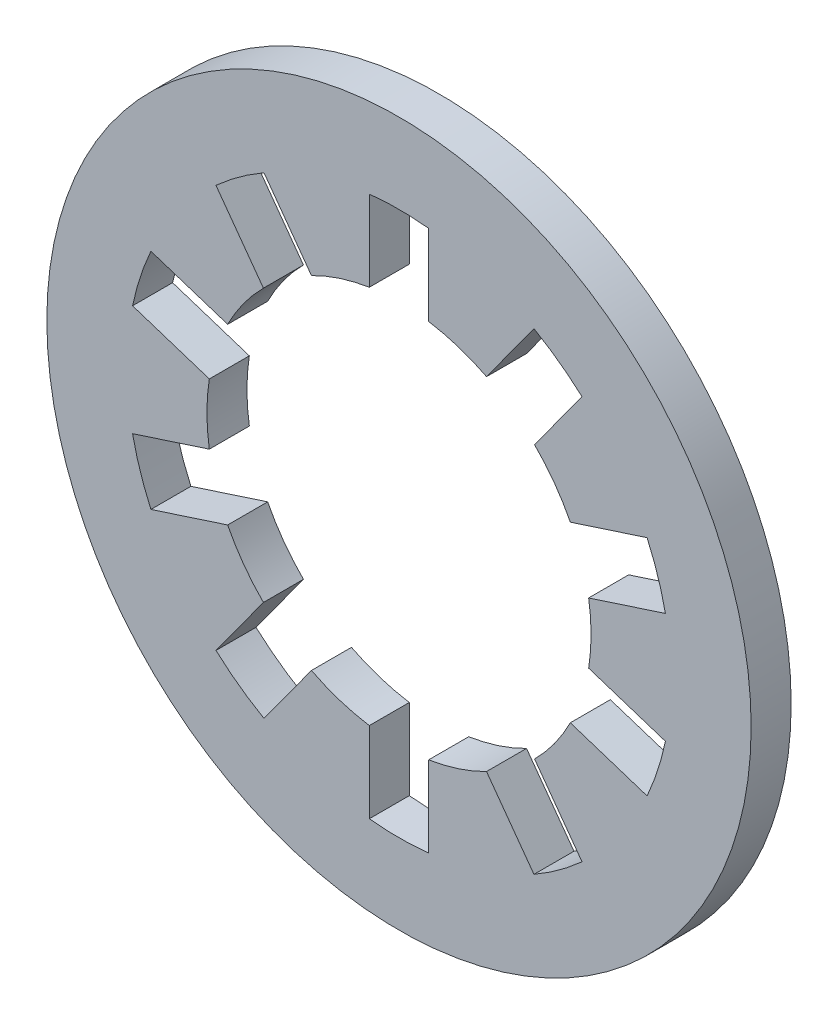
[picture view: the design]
ISO-10303-21;
HEADER;
FILE_DESCRIPTION(('STEP AP214'),'2;1');
FILE_NAME('part.step','',(''),(''),'','','');
FILE_SCHEMA(('AUTOMOTIVE_DESIGN { 1 0 10303 214 1 1 1 1 }'));
ENDSEC;
DATA;
#1=APPLICATION_CONTEXT('core data for automotive mechanical design processes');
#2=APPLICATION_PROTOCOL_DEFINITION('international standard','automotive_design',2000,#1);
#3=PRODUCT_CONTEXT('',#1,'mechanical');
#4=PRODUCT('Part','Part','',(#3));
#5=PRODUCT_RELATED_PRODUCT_CATEGORY('part','',(#4));
#6=PRODUCT_DEFINITION_FORMATION('','',#4);
#7=PRODUCT_DEFINITION_CONTEXT('part definition',#1,'design');
#8=PRODUCT_DEFINITION('design','',#6,#7);
#9=PRODUCT_DEFINITION_SHAPE('','',#8);
#10=(LENGTH_UNIT() NAMED_UNIT(*) SI_UNIT(.MILLI.,.METRE.));
#11=(NAMED_UNIT(*) PLANE_ANGLE_UNIT() SI_UNIT($,.RADIAN.));
#12=(NAMED_UNIT(*) SI_UNIT($,.STERADIAN.) SOLID_ANGLE_UNIT());
#13=UNCERTAINTY_MEASURE_WITH_UNIT(LENGTH_MEASURE(1.E-05),#10,'distance_accuracy_value','');
#14=(GEOMETRIC_REPRESENTATION_CONTEXT(3) GLOBAL_UNCERTAINTY_ASSIGNED_CONTEXT((#13)) GLOBAL_UNIT_ASSIGNED_CONTEXT((#10,
#11,#12)) REPRESENTATION_CONTEXT('',''));
#15=CARTESIAN_POINT('',(0.,0.,0.));
#16=DIRECTION('',(0.,0.,1.));
#17=DIRECTION('',(1.,0.,0.));
#18=AXIS2_PLACEMENT_3D('',#15,#16,#17);
#19=CARTESIAN_POINT('',(0.,0.,0.25));
#20=DIRECTION('',(0.,0.,1.));
#21=DIRECTION('',(1.,0.,0.));
#22=AXIS2_PLACEMENT_3D('',#19,#20,#21);
#23=PLANE('',#22);
#24=CARTESIAN_POINT('',(0.,0.,0.25));
#25=DIRECTION('',(0.,0.,1.));
#26=DIRECTION('',(1.,0.,0.));
#27=AXIS2_PLACEMENT_3D('',#24,#25,#26);
#28=CIRCLE('',#27,2.2);
#29=CARTESIAN_POINT('',(2.2,0.,0.25));
#30=VERTEX_POINT('',#29);
#31=EDGE_CURVE('E11',#30,#30,#28,.T.);
#32=ORIENTED_EDGE('',*,*,#31,.T.);
#33=EDGE_LOOP('',(#32));
#34=FACE_BOUND('',#33,.T.);
#35=CARTESIAN_POINT('',(0.,0.,0.25));
#36=DIRECTION('',(0.,0.,1.));
#37=DIRECTION('',(1.,0.,0.));
#38=AXIS2_PLACEMENT_3D('',#35,#36,#37);
#39=CIRCLE('',#38,1.2);
#40=CARTESIAN_POINT('',(-0.846872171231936,0.850180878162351,0.25));
#41=VERTEX_POINT('',#40);
#42=CARTESIAN_POINT('',(-1.07026795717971,0.542702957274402,0.25));
#43=VERTEX_POINT('',#42);
#44=EDGE_CURVE('E316',#41,#43,#39,.T.);
#45=ORIENTED_EDGE('',*,*,#44,.F.);
#46=DIRECTION('',(0.587785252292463,-0.809016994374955,0.));
#47=VECTOR('',#46,1.);
#48=CARTESIAN_POINT('',(-1.14327413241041,1.25814317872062,0.25));
#49=LINE('',#48,#47);
#50=CARTESIAN_POINT('',(-1.14327413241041,1.25814317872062,0.25));
#51=VERTEX_POINT('',#50);
#52=EDGE_CURVE('E305',#51,#41,#49,.T.);
#53=ORIENTED_EDGE('',*,*,#52,.F.);
#54=CARTESIAN_POINT('',(0.,0.,0.25));
#55=DIRECTION('',(0.,0.,1.));
#56=DIRECTION('',(0.809016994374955,0.587785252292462,0.));
#57=AXIS2_PLACEMENT_3D('',#54,#55,#56);
#58=CIRCLE('',#57,1.7);
#59=CARTESIAN_POINT('',(-0.84327413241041,1.47610593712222,0.25));
#60=VERTEX_POINT('',#59);
#61=EDGE_CURVE('E295',#60,#51,#58,.T.);
#62=ORIENTED_EDGE('',*,*,#61,.F.);
#63=DIRECTION('',(-0.587785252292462,0.809016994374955,0.));
#64=VECTOR('',#63,1.);
#65=CARTESIAN_POINT('',(-0.84327413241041,1.47610593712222,0.25));
#66=LINE('',#65,#64);
#67=CARTESIAN_POINT('',(-0.546872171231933,1.06814363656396,0.25));
#68=VERTEX_POINT('',#67);
#69=EDGE_CURVE('E317',#68,#60,#66,.T.);
#70=ORIENTED_EDGE('',*,*,#69,.F.);
#71=CARTESIAN_POINT('',(-0.185410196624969,1.18558975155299,0.25));
#72=VERTEX_POINT('',#71);
#73=EDGE_CURVE('E553',#72,#68,#39,.T.);
#74=ORIENTED_EDGE('',*,*,#73,.F.);
#75=DIRECTION('',(0.,-1.,0.));
#76=VECTOR('',#75,1.);
#77=CARTESIAN_POINT('',(-0.185410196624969,1.68985888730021,0.25));
#78=LINE('',#77,#76);
#79=CARTESIAN_POINT('',(-0.185410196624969,1.68985888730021,0.25));
#80=VERTEX_POINT('',#79);
#81=EDGE_CURVE('E530',#80,#72,#78,.T.);
#82=ORIENTED_EDGE('',*,*,#81,.F.);
#83=CARTESIAN_POINT('',(0.,0.,0.25));
#84=DIRECTION('',(0.,0.,1.));
#85=DIRECTION('',(1.,0.,0.));
#86=AXIS2_PLACEMENT_3D('',#83,#84,#85);
#87=CIRCLE('',#86,1.7);
#88=CARTESIAN_POINT('',(0.185410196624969,1.68985888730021,0.25));
#89=VERTEX_POINT('',#88);
#90=EDGE_CURVE('E528',#89,#80,#87,.T.);
#91=ORIENTED_EDGE('',*,*,#90,.F.);
#92=DIRECTION('',(0.,1.,0.));
#93=VECTOR('',#92,1.);
#94=CARTESIAN_POINT('',(0.185410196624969,1.68985888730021,0.25));
#95=LINE('',#94,#93);
#96=CARTESIAN_POINT('',(0.185410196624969,1.18558975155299,0.25));
#97=VERTEX_POINT('',#96);
#98=EDGE_CURVE('E533',#97,#89,#95,.T.);
#99=ORIENTED_EDGE('',*,*,#98,.F.);
#100=CARTESIAN_POINT('',(0.546872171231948,1.06814363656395,0.25));
#101=VERTEX_POINT('',#100);
#102=EDGE_CURVE('E556',#101,#97,#39,.T.);
#103=ORIENTED_EDGE('',*,*,#102,.F.);
#104=DIRECTION('',(-0.587785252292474,-0.809016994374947,0.));
#105=VECTOR('',#104,1.);
#106=CARTESIAN_POINT('',(0.843274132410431,1.47610593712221,0.25));
#107=LINE('',#106,#105);
#108=CARTESIAN_POINT('',(0.843274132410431,1.47610593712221,0.25));
#109=VERTEX_POINT('',#108);
#110=EDGE_CURVE('E505',#109,#101,#107,.T.);
#111=ORIENTED_EDGE('',*,*,#110,.F.);
#112=CARTESIAN_POINT('',(0.,0.,0.25));
#113=DIRECTION('',(0.,0.,1.));
#114=DIRECTION('',(0.809016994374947,-0.587785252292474,0.));
#115=AXIS2_PLACEMENT_3D('',#112,#113,#114);
#116=CIRCLE('',#115,1.7);
#117=CARTESIAN_POINT('',(1.14327413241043,1.2581431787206,0.25));
#118=VERTEX_POINT('',#117);
#119=EDGE_CURVE('E503',#118,#109,#116,.T.);
#120=ORIENTED_EDGE('',*,*,#119,.F.);
#121=DIRECTION('',(0.587785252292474,0.809016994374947,0.));
#122=VECTOR('',#121,1.);
#123=CARTESIAN_POINT('',(1.14327413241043,1.2581431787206,0.25));
#124=LINE('',#123,#122);
#125=CARTESIAN_POINT('',(0.846872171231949,0.850180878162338,0.25));
#126=VERTEX_POINT('',#125);
#127=EDGE_CURVE('E508',#126,#118,#124,.T.);
#128=ORIENTED_EDGE('',*,*,#127,.F.);
#129=CARTESIAN_POINT('',(1.07026795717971,0.542702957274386,0.25));
#130=VERTEX_POINT('',#129);
#131=EDGE_CURVE('E560',#130,#126,#39,.T.);
#132=ORIENTED_EDGE('',*,*,#131,.F.);
#133=DIRECTION('',(-0.951056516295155,-0.309016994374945,0.));
#134=VECTOR('',#133,1.);
#135=CARTESIAN_POINT('',(1.54985640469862,0.698530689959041,0.25));
#136=LINE('',#135,#134);
#137=CARTESIAN_POINT('',(1.54985640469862,0.698530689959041,0.25));
#138=VERTEX_POINT('',#137);
#139=EDGE_CURVE('E480',#138,#130,#136,.T.);
#140=ORIENTED_EDGE('',*,*,#139,.F.);
#141=CARTESIAN_POINT('',(0.,0.,0.25));
#142=DIRECTION('',(0.,0.,1.));
#143=DIRECTION('',(0.309016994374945,-0.951056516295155,0.));
#144=AXIS2_PLACEMENT_3D('',#141,#142,#143);
#145=CIRCLE('',#144,1.7);
#146=CARTESIAN_POINT('',(1.66444620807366,0.345859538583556,0.25));
#147=VERTEX_POINT('',#146);
#148=EDGE_CURVE('E478',#147,#138,#145,.T.);
#149=ORIENTED_EDGE('',*,*,#148,.F.);
#150=DIRECTION('',(0.951056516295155,0.309016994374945,0.));
#151=VECTOR('',#150,1.);
#152=CARTESIAN_POINT('',(1.66444620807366,0.345859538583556,0.25));
#153=LINE('',#152,#151);
#154=CARTESIAN_POINT('',(1.18485776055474,0.190031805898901,0.25));
#155=VERTEX_POINT('',#154);
#156=EDGE_CURVE('E483',#155,#147,#153,.T.);
#157=ORIENTED_EDGE('',*,*,#156,.F.);
#158=CARTESIAN_POINT('',(1.18485776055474,-0.19003180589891,0.25));
#159=VERTEX_POINT('',#158);
#160=EDGE_CURVE('E613',#159,#155,#39,.T.);
#161=ORIENTED_EDGE('',*,*,#160,.F.);
#162=DIRECTION('',(-0.951056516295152,0.309016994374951,0.));
#163=VECTOR('',#162,1.);
#164=CARTESIAN_POINT('',(1.66444620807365,-0.345859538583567,0.25));
#165=LINE('',#164,#163);
#166=CARTESIAN_POINT('',(1.66444620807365,-0.345859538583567,0.25));
#167=VERTEX_POINT('',#166);
#168=EDGE_CURVE('E455',#167,#159,#165,.T.);
#169=ORIENTED_EDGE('',*,*,#168,.F.);
#170=CARTESIAN_POINT('',(0.,0.,0.25));
#171=DIRECTION('',(0.,0.,1.));
#172=DIRECTION('',(-0.309016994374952,-0.951056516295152,0.));
#173=AXIS2_PLACEMENT_3D('',#170,#171,#172);
#174=CIRCLE('',#173,1.7);
#175=CARTESIAN_POINT('',(1.54985640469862,-0.698530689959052,0.25));
#176=VERTEX_POINT('',#175);
#177=EDGE_CURVE('E453',#176,#167,#174,.T.);
#178=ORIENTED_EDGE('',*,*,#177,.F.);
#179=DIRECTION('',(0.951056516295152,-0.309016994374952,0.));
#180=VECTOR('',#179,1.);
#181=CARTESIAN_POINT('',(1.54985640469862,-0.698530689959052,0.25));
#182=LINE('',#181,#180);
#183=CARTESIAN_POINT('',(1.07026795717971,-0.542702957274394,0.25));
#184=VERTEX_POINT('',#183);
#185=EDGE_CURVE('E458',#184,#176,#182,.T.);
#186=ORIENTED_EDGE('',*,*,#185,.F.);
#187=CARTESIAN_POINT('',(0.846872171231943,-0.850180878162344,0.25));
#188=VERTEX_POINT('',#187);
#189=EDGE_CURVE('E608',#188,#184,#39,.T.);
#190=ORIENTED_EDGE('',*,*,#189,.F.);
#191=DIRECTION('',(-0.587785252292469,0.809016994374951,0.));
#192=VECTOR('',#191,1.);
#193=CARTESIAN_POINT('',(1.14327413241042,-1.25814317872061,0.25));
#194=LINE('',#193,#192);
#195=CARTESIAN_POINT('',(1.14327413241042,-1.25814317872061,0.25));
#196=VERTEX_POINT('',#195);
#197=EDGE_CURVE('E430',#196,#188,#194,.T.);
#198=ORIENTED_EDGE('',*,*,#197,.F.);
#199=CARTESIAN_POINT('',(0.,0.,0.25));
#200=DIRECTION('',(0.,0.,1.));
#201=DIRECTION('',(-0.809016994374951,-0.587785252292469,0.));
#202=AXIS2_PLACEMENT_3D('',#199,#200,#201);
#203=CIRCLE('',#202,1.7);
#204=CARTESIAN_POINT('',(0.843274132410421,-1.47610593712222,0.25));
#205=VERTEX_POINT('',#204);
#206=EDGE_CURVE('E428',#205,#196,#203,.T.);
#207=ORIENTED_EDGE('',*,*,#206,.F.);
#208=DIRECTION('',(0.587785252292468,-0.809016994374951,0.));
#209=VECTOR('',#208,1.);
#210=CARTESIAN_POINT('',(0.843274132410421,-1.47610593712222,0.25));
#211=LINE('',#210,#209);
#212=CARTESIAN_POINT('',(0.546872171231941,-1.06814363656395,0.25));
#213=VERTEX_POINT('',#212);
#214=EDGE_CURVE('E433',#213,#205,#211,.T.);
#215=ORIENTED_EDGE('',*,*,#214,.F.);
#216=CARTESIAN_POINT('',(0.185410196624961,-1.185589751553,0.25));
#217=VERTEX_POINT('',#216);
#218=EDGE_CURVE('E603',#217,#213,#39,.T.);
#219=ORIENTED_EDGE('',*,*,#218,.F.);
#220=DIRECTION('',(0.,1.,0.));
#221=VECTOR('',#220,1.);
#222=CARTESIAN_POINT('',(0.185410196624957,-1.68985888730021,0.25));
#223=LINE('',#222,#221);
#224=CARTESIAN_POINT('',(0.185410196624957,-1.68985888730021,0.25));
#225=VERTEX_POINT('',#224);
#226=EDGE_CURVE('E405',#225,#217,#223,.T.);
#227=ORIENTED_EDGE('',*,*,#226,.F.);
#228=CARTESIAN_POINT('',(0.,0.,0.25));
#229=DIRECTION('',(0.,0.,1.));
#230=DIRECTION('',(-1.,0.,0.));
#231=AXIS2_PLACEMENT_3D('',#228,#229,#230);
#232=CIRCLE('',#231,1.7);
#233=CARTESIAN_POINT('',(-0.185410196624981,-1.6898588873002,0.25));
#234=VERTEX_POINT('',#233);
#235=EDGE_CURVE('E403',#234,#225,#232,.T.);
#236=ORIENTED_EDGE('',*,*,#235,.F.);
#237=DIRECTION('',(0.,-1.,0.));
#238=VECTOR('',#237,1.);
#239=CARTESIAN_POINT('',(-0.185410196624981,-1.6898588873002,0.25));
#240=LINE('',#239,#238);
#241=CARTESIAN_POINT('',(-0.185410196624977,-1.18558975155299,0.25));
#242=VERTEX_POINT('',#241);
#243=EDGE_CURVE('E408',#242,#234,#240,.T.);
#244=ORIENTED_EDGE('',*,*,#243,.F.);
#245=CARTESIAN_POINT('',(-0.546872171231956,-1.06814363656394,0.25));
#246=VERTEX_POINT('',#245);
#247=EDGE_CURVE('E598',#246,#242,#39,.T.);
#248=ORIENTED_EDGE('',*,*,#247,.F.);
#249=DIRECTION('',(0.58778525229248,0.809016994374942,0.));
#250=VECTOR('',#249,1.);
#251=CARTESIAN_POINT('',(-0.843274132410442,-1.4761059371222,0.25));
#252=LINE('',#251,#250);
#253=CARTESIAN_POINT('',(-0.843274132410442,-1.4761059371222,0.25));
#254=VERTEX_POINT('',#253);
#255=EDGE_CURVE('E380',#254,#246,#252,.T.);
#256=ORIENTED_EDGE('',*,*,#255,.F.);
#257=CARTESIAN_POINT('',(0.,0.,0.25));
#258=DIRECTION('',(0.,0.,1.));
#259=DIRECTION('',(-0.809016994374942,0.58778525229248,0.));
#260=AXIS2_PLACEMENT_3D('',#257,#258,#259);
#261=CIRCLE('',#260,1.7);
#262=CARTESIAN_POINT('',(-1.14327413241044,-1.25814317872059,0.25));
#263=VERTEX_POINT('',#262);
#264=EDGE_CURVE('E378',#263,#254,#261,.T.);
#265=ORIENTED_EDGE('',*,*,#264,.F.);
#266=DIRECTION('',(-0.58778525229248,-0.809016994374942,0.));
#267=VECTOR('',#266,1.);
#268=CARTESIAN_POINT('',(-1.14327413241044,-1.25814317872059,0.25));
#269=LINE('',#268,#267);
#270=CARTESIAN_POINT('',(-0.846872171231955,-0.850180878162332,0.25));
#271=VERTEX_POINT('',#270);
#272=EDGE_CURVE('E383',#271,#263,#269,.T.);
#273=ORIENTED_EDGE('',*,*,#272,.F.);
#274=CARTESIAN_POINT('',(-1.07026795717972,-0.542702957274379,0.25));
#275=VERTEX_POINT('',#274);
#276=EDGE_CURVE('E597',#275,#271,#39,.T.);
#277=ORIENTED_EDGE('',*,*,#276,.F.);
#278=DIRECTION('',(0.951056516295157,0.309016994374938,0.));
#279=VECTOR('',#278,1.);
#280=CARTESIAN_POINT('',(-1.54985640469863,-0.69853068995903,0.25));
#281=LINE('',#280,#279);
#282=CARTESIAN_POINT('',(-1.54985640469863,-0.69853068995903,0.25));
#283=VERTEX_POINT('',#282);
#284=EDGE_CURVE('E355',#283,#275,#281,.T.);
#285=ORIENTED_EDGE('',*,*,#284,.F.);
#286=CARTESIAN_POINT('',(0.,0.,0.25));
#287=DIRECTION('',(0.,0.,1.));
#288=DIRECTION('',(-0.309016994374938,0.951056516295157,0.));
#289=AXIS2_PLACEMENT_3D('',#286,#287,#288);
#290=CIRCLE('',#289,1.7);
#291=CARTESIAN_POINT('',(-1.66444620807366,-0.345859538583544,0.25));
#292=VERTEX_POINT('',#291);
#293=EDGE_CURVE('E353',#292,#283,#290,.T.);
#294=ORIENTED_EDGE('',*,*,#293,.F.);
#295=DIRECTION('',(-0.951056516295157,-0.309016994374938,0.));
#296=VECTOR('',#295,1.);
#297=CARTESIAN_POINT('',(-1.66444620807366,-0.345859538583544,0.25));
#298=LINE('',#297,#296);
#299=CARTESIAN_POINT('',(-1.18485776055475,-0.190031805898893,0.25));
#300=VERTEX_POINT('',#299);
#301=EDGE_CURVE('E358',#300,#292,#298,.T.);
#302=ORIENTED_EDGE('',*,*,#301,.F.);
#303=CARTESIAN_POINT('',(-1.18485776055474,0.190031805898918,0.25));
#304=VERTEX_POINT('',#303);
#305=EDGE_CURVE('E595',#304,#300,#39,.T.);
#306=ORIENTED_EDGE('',*,*,#305,.F.);
#307=DIRECTION('',(0.95105651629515,-0.309016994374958,0.));
#308=VECTOR('',#307,1.);
#309=CARTESIAN_POINT('',(-1.66444620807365,0.345859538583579,0.25));
#310=LINE('',#309,#308);
#311=CARTESIAN_POINT('',(-1.66444620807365,0.345859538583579,0.25));
#312=VERTEX_POINT('',#311);
#313=EDGE_CURVE('E331',#312,#304,#310,.T.);
#314=ORIENTED_EDGE('',*,*,#313,.F.);
#315=CARTESIAN_POINT('',(0.,0.,0.25));
#316=DIRECTION('',(0.,0.,1.));
#317=DIRECTION('',(0.309016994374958,0.95105651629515,0.));
#318=AXIS2_PLACEMENT_3D('',#315,#316,#317);
#319=CIRCLE('',#318,1.7);
#320=CARTESIAN_POINT('',(-1.54985640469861,0.698530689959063,0.25));
#321=VERTEX_POINT('',#320);
#322=EDGE_CURVE('E329',#321,#312,#319,.T.);
#323=ORIENTED_EDGE('',*,*,#322,.F.);
#324=DIRECTION('',(-0.95105651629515,0.309016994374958,0.));
#325=VECTOR('',#324,1.);
#326=CARTESIAN_POINT('',(-1.54985640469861,0.698530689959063,0.25));
#327=LINE('',#326,#325);
#328=EDGE_CURVE('E334',#43,#321,#327,.T.);
#329=ORIENTED_EDGE('',*,*,#328,.F.);
#330=EDGE_LOOP('',(#45,#53,#62,#70,#74,#82,#91,#99,#103,#111,#120,#128,#132,#140,#149,#157,#161,
#169,#178,#186,#190,#198,#207,#215,#219,#227,#236,#244,#248,#256,#265,#273,#277,#285,#294,#302,
#306,#314,#323,#329));
#331=FACE_BOUND('',#330,.T.);
#332=ADVANCED_FACE('F35',(#34,#331),#23,.T.);
#333=CARTESIAN_POINT('',(0.,0.,0.));
#334=DIRECTION('',(0.,0.,1.));
#335=DIRECTION('',(1.,0.,0.));
#336=AXIS2_PLACEMENT_3D('',#333,#334,#335);
#337=PLANE('',#336);
#338=CARTESIAN_POINT('',(0.,0.,0.));
#339=DIRECTION('',(0.,0.,1.));
#340=DIRECTION('',(1.,0.,0.));
#341=AXIS2_PLACEMENT_3D('',#338,#339,#340);
#342=CIRCLE('',#341,2.2);
#343=CARTESIAN_POINT('',(2.2,0.,0.));
#344=VERTEX_POINT('',#343);
#345=EDGE_CURVE('E39',#344,#344,#342,.T.);
#346=ORIENTED_EDGE('',*,*,#345,.F.);
#347=EDGE_LOOP('',(#346));
#348=FACE_BOUND('',#347,.T.);
#349=DIRECTION('',(0.587785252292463,-0.809016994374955,0.));
#350=VECTOR('',#349,1.);
#351=CARTESIAN_POINT('',(-1.14327413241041,1.25814317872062,0.));
#352=LINE('',#351,#350);
#353=CARTESIAN_POINT('',(-1.14327413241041,1.25814317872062,0.));
#354=VERTEX_POINT('',#353);
#355=CARTESIAN_POINT('',(-0.846872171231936,0.850180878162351,0.));
#356=VERTEX_POINT('',#355);
#357=EDGE_CURVE('E310',#354,#356,#352,.T.);
#358=ORIENTED_EDGE('',*,*,#357,.T.);
#359=CARTESIAN_POINT('',(0.,0.,0.));
#360=DIRECTION('',(0.,0.,1.));
#361=DIRECTION('',(1.,0.,0.));
#362=AXIS2_PLACEMENT_3D('',#359,#360,#361);
#363=CIRCLE('',#362,1.2);
#364=CARTESIAN_POINT('',(-1.07026795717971,0.542702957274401,0.));
#365=VERTEX_POINT('',#364);
#366=EDGE_CURVE('E58',#356,#365,#363,.T.);
#367=ORIENTED_EDGE('',*,*,#366,.T.);
#368=DIRECTION('',(-0.95105651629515,0.309016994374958,0.));
#369=VECTOR('',#368,1.);
#370=CARTESIAN_POINT('',(-1.54985640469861,0.698530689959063,0.));
#371=LINE('',#370,#369);
#372=CARTESIAN_POINT('',(-1.54985640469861,0.698530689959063,0.));
#373=VERTEX_POINT('',#372);
#374=EDGE_CURVE('E332',#365,#373,#371,.T.);
#375=ORIENTED_EDGE('',*,*,#374,.T.);
#376=CARTESIAN_POINT('',(0.,0.,0.));
#377=DIRECTION('',(0.,0.,1.));
#378=DIRECTION('',(0.309016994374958,0.95105651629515,0.));
#379=AXIS2_PLACEMENT_3D('',#376,#377,#378);
#380=CIRCLE('',#379,1.7);
#381=CARTESIAN_POINT('',(-1.66444620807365,0.345859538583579,0.));
#382=VERTEX_POINT('',#381);
#383=EDGE_CURVE('E311',#373,#382,#380,.T.);
#384=ORIENTED_EDGE('',*,*,#383,.T.);
#385=DIRECTION('',(0.95105651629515,-0.309016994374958,0.));
#386=VECTOR('',#385,1.);
#387=CARTESIAN_POINT('',(-1.66444620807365,0.345859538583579,0.));
#388=LINE('',#387,#386);
#389=CARTESIAN_POINT('',(-1.18485776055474,0.190031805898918,0.));
#390=VERTEX_POINT('',#389);
#391=EDGE_CURVE('E339',#382,#390,#388,.T.);
#392=ORIENTED_EDGE('',*,*,#391,.T.);
#393=CARTESIAN_POINT('',(-1.18485776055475,-0.190031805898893,0.));
#394=VERTEX_POINT('',#393);
#395=EDGE_CURVE('E561',#390,#394,#363,.T.);
#396=ORIENTED_EDGE('',*,*,#395,.T.);
#397=DIRECTION('',(-0.951056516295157,-0.309016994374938,0.));
#398=VECTOR('',#397,1.);
#399=CARTESIAN_POINT('',(-1.66444620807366,-0.345859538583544,0.));
#400=LINE('',#399,#398);
#401=CARTESIAN_POINT('',(-1.66444620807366,-0.345859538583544,0.));
#402=VERTEX_POINT('',#401);
#403=EDGE_CURVE('E356',#394,#402,#400,.T.);
#404=ORIENTED_EDGE('',*,*,#403,.T.);
#405=CARTESIAN_POINT('',(0.,0.,0.));
#406=DIRECTION('',(0.,0.,1.));
#407=DIRECTION('',(-0.309016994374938,0.951056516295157,0.));
#408=AXIS2_PLACEMENT_3D('',#405,#406,#407);
#409=CIRCLE('',#408,1.7);
#410=CARTESIAN_POINT('',(-1.54985640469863,-0.69853068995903,0.));
#411=VERTEX_POINT('',#410);
#412=EDGE_CURVE('E352',#402,#411,#409,.T.);
#413=ORIENTED_EDGE('',*,*,#412,.T.);
#414=DIRECTION('',(0.951056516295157,0.309016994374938,0.));
#415=VECTOR('',#414,1.);
#416=CARTESIAN_POINT('',(-1.54985640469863,-0.69853068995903,0.));
#417=LINE('',#416,#415);
#418=CARTESIAN_POINT('',(-1.07026795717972,-0.542702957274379,0.));
#419=VERTEX_POINT('',#418);
#420=EDGE_CURVE('E363',#411,#419,#417,.T.);
#421=ORIENTED_EDGE('',*,*,#420,.T.);
#422=CARTESIAN_POINT('',(-0.846872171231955,-0.850180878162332,0.));
#423=VERTEX_POINT('',#422);
#424=EDGE_CURVE('E577',#419,#423,#363,.T.);
#425=ORIENTED_EDGE('',*,*,#424,.T.);
#426=DIRECTION('',(-0.58778525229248,-0.809016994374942,0.));
#427=VECTOR('',#426,1.);
#428=CARTESIAN_POINT('',(-1.14327413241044,-1.25814317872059,0.));
#429=LINE('',#428,#427);
#430=CARTESIAN_POINT('',(-1.14327413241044,-1.25814317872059,0.));
#431=VERTEX_POINT('',#430);
#432=EDGE_CURVE('E381',#423,#431,#429,.T.);
#433=ORIENTED_EDGE('',*,*,#432,.T.);
#434=CARTESIAN_POINT('',(0.,0.,0.));
#435=DIRECTION('',(0.,0.,1.));
#436=DIRECTION('',(-0.809016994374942,0.58778525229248,0.));
#437=AXIS2_PLACEMENT_3D('',#434,#435,#436);
#438=CIRCLE('',#437,1.7);
#439=CARTESIAN_POINT('',(-0.843274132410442,-1.4761059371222,0.));
#440=VERTEX_POINT('',#439);
#441=EDGE_CURVE('E377',#431,#440,#438,.T.);
#442=ORIENTED_EDGE('',*,*,#441,.T.);
#443=DIRECTION('',(0.58778525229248,0.809016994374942,0.));
#444=VECTOR('',#443,1.);
#445=CARTESIAN_POINT('',(-0.843274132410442,-1.4761059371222,0.));
#446=LINE('',#445,#444);
#447=CARTESIAN_POINT('',(-0.546872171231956,-1.06814363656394,0.));
#448=VERTEX_POINT('',#447);
#449=EDGE_CURVE('E388',#440,#448,#446,.T.);
#450=ORIENTED_EDGE('',*,*,#449,.T.);
#451=CARTESIAN_POINT('',(-0.185410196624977,-1.18558975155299,0.));
#452=VERTEX_POINT('',#451);
#453=EDGE_CURVE('E574',#448,#452,#363,.T.);
#454=ORIENTED_EDGE('',*,*,#453,.T.);
#455=DIRECTION('',(0.,-1.,0.));
#456=VECTOR('',#455,1.);
#457=CARTESIAN_POINT('',(-0.185410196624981,-1.6898588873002,0.));
#458=LINE('',#457,#456);
#459=CARTESIAN_POINT('',(-0.185410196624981,-1.6898588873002,0.));
#460=VERTEX_POINT('',#459);
#461=EDGE_CURVE('E406',#452,#460,#458,.T.);
#462=ORIENTED_EDGE('',*,*,#461,.T.);
#463=CARTESIAN_POINT('',(0.,0.,0.));
#464=DIRECTION('',(0.,0.,1.));
#465=DIRECTION('',(-1.,0.,0.));
#466=AXIS2_PLACEMENT_3D('',#463,#464,#465);
#467=CIRCLE('',#466,1.7);
#468=CARTESIAN_POINT('',(0.185410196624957,-1.68985888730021,0.));
#469=VERTEX_POINT('',#468);
#470=EDGE_CURVE('E402',#460,#469,#467,.T.);
#471=ORIENTED_EDGE('',*,*,#470,.T.);
#472=DIRECTION('',(0.,1.,0.));
#473=VECTOR('',#472,1.);
#474=CARTESIAN_POINT('',(0.185410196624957,-1.68985888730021,0.));
#475=LINE('',#474,#473);
#476=CARTESIAN_POINT('',(0.185410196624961,-1.185589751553,0.));
#477=VERTEX_POINT('',#476);
#478=EDGE_CURVE('E413',#469,#477,#475,.T.);
#479=ORIENTED_EDGE('',*,*,#478,.T.);
#480=CARTESIAN_POINT('',(0.546872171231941,-1.06814363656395,0.));
#481=VERTEX_POINT('',#480);
#482=EDGE_CURVE('E571',#477,#481,#363,.T.);
#483=ORIENTED_EDGE('',*,*,#482,.T.);
#484=DIRECTION('',(0.587785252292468,-0.809016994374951,0.));
#485=VECTOR('',#484,1.);
#486=CARTESIAN_POINT('',(0.843274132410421,-1.47610593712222,0.));
#487=LINE('',#486,#485);
#488=CARTESIAN_POINT('',(0.843274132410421,-1.47610593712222,0.));
#489=VERTEX_POINT('',#488);
#490=EDGE_CURVE('E431',#481,#489,#487,.T.);
#491=ORIENTED_EDGE('',*,*,#490,.T.);
#492=CARTESIAN_POINT('',(0.,0.,0.));
#493=DIRECTION('',(0.,0.,1.));
#494=DIRECTION('',(-0.809016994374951,-0.587785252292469,0.));
#495=AXIS2_PLACEMENT_3D('',#492,#493,#494);
#496=CIRCLE('',#495,1.7);
#497=CARTESIAN_POINT('',(1.14327413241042,-1.25814317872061,0.));
#498=VERTEX_POINT('',#497);
#499=EDGE_CURVE('E427',#489,#498,#496,.T.);
#500=ORIENTED_EDGE('',*,*,#499,.T.);
#501=DIRECTION('',(-0.587785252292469,0.809016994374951,0.));
#502=VECTOR('',#501,1.);
#503=CARTESIAN_POINT('',(1.14327413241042,-1.25814317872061,0.));
#504=LINE('',#503,#502);
#505=CARTESIAN_POINT('',(0.846872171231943,-0.850180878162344,0.));
#506=VERTEX_POINT('',#505);
#507=EDGE_CURVE('E438',#498,#506,#504,.T.);
#508=ORIENTED_EDGE('',*,*,#507,.T.);
#509=CARTESIAN_POINT('',(1.07026795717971,-0.542702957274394,0.));
#510=VERTEX_POINT('',#509);
#511=EDGE_CURVE('E568',#506,#510,#363,.T.);
#512=ORIENTED_EDGE('',*,*,#511,.T.);
#513=DIRECTION('',(0.951056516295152,-0.309016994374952,0.));
#514=VECTOR('',#513,1.);
#515=CARTESIAN_POINT('',(1.54985640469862,-0.698530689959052,0.));
#516=LINE('',#515,#514);
#517=CARTESIAN_POINT('',(1.54985640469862,-0.698530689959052,0.));
#518=VERTEX_POINT('',#517);
#519=EDGE_CURVE('E456',#510,#518,#516,.T.);
#520=ORIENTED_EDGE('',*,*,#519,.T.);
#521=CARTESIAN_POINT('',(0.,0.,0.));
#522=DIRECTION('',(0.,0.,1.));
#523=DIRECTION('',(-0.309016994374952,-0.951056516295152,0.));
#524=AXIS2_PLACEMENT_3D('',#521,#522,#523);
#525=CIRCLE('',#524,1.7);
#526=CARTESIAN_POINT('',(1.66444620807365,-0.345859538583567,0.));
#527=VERTEX_POINT('',#526);
#528=EDGE_CURVE('E452',#518,#527,#525,.T.);
#529=ORIENTED_EDGE('',*,*,#528,.T.);
#530=DIRECTION('',(-0.951056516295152,0.309016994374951,0.));
#531=VECTOR('',#530,1.);
#532=CARTESIAN_POINT('',(1.66444620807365,-0.345859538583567,0.));
#533=LINE('',#532,#531);
#534=CARTESIAN_POINT('',(1.18485776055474,-0.19003180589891,0.));
#535=VERTEX_POINT('',#534);
#536=EDGE_CURVE('E463',#527,#535,#533,.T.);
#537=ORIENTED_EDGE('',*,*,#536,.T.);
#538=CARTESIAN_POINT('',(1.18485776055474,0.190031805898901,0.));
#539=VERTEX_POINT('',#538);
#540=EDGE_CURVE('E565',#535,#539,#363,.T.);
#541=ORIENTED_EDGE('',*,*,#540,.T.);
#542=DIRECTION('',(0.951056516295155,0.309016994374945,0.));
#543=VECTOR('',#542,1.);
#544=CARTESIAN_POINT('',(1.66444620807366,0.345859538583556,0.));
#545=LINE('',#544,#543);
#546=CARTESIAN_POINT('',(1.66444620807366,0.345859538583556,0.));
#547=VERTEX_POINT('',#546);
#548=EDGE_CURVE('E481',#539,#547,#545,.T.);
#549=ORIENTED_EDGE('',*,*,#548,.T.);
#550=CARTESIAN_POINT('',(0.,0.,0.));
#551=DIRECTION('',(0.,0.,1.));
#552=DIRECTION('',(0.309016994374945,-0.951056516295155,0.));
#553=AXIS2_PLACEMENT_3D('',#550,#551,#552);
#554=CIRCLE('',#553,1.7);
#555=CARTESIAN_POINT('',(1.54985640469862,0.698530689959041,0.));
#556=VERTEX_POINT('',#555);
#557=EDGE_CURVE('E477',#547,#556,#554,.T.);
#558=ORIENTED_EDGE('',*,*,#557,.T.);
#559=DIRECTION('',(-0.951056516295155,-0.309016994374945,0.));
#560=VECTOR('',#559,1.);
#561=CARTESIAN_POINT('',(1.54985640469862,0.698530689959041,0.));
#562=LINE('',#561,#560);
#563=CARTESIAN_POINT('',(1.07026795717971,0.542702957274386,0.));
#564=VERTEX_POINT('',#563);
#565=EDGE_CURVE('E488',#556,#564,#562,.T.);
#566=ORIENTED_EDGE('',*,*,#565,.T.);
#567=CARTESIAN_POINT('',(0.846872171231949,0.850180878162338,0.));
#568=VERTEX_POINT('',#567);
#569=EDGE_CURVE('E562',#564,#568,#363,.T.);
#570=ORIENTED_EDGE('',*,*,#569,.T.);
#571=DIRECTION('',(0.587785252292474,0.809016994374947,0.));
#572=VECTOR('',#571,1.);
#573=CARTESIAN_POINT('',(1.14327413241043,1.2581431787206,0.));
#574=LINE('',#573,#572);
#575=CARTESIAN_POINT('',(1.14327413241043,1.2581431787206,0.));
#576=VERTEX_POINT('',#575);
#577=EDGE_CURVE('E506',#568,#576,#574,.T.);
#578=ORIENTED_EDGE('',*,*,#577,.T.);
#579=CARTESIAN_POINT('',(0.,0.,0.));
#580=DIRECTION('',(0.,0.,1.));
#581=DIRECTION('',(0.809016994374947,-0.587785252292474,0.));
#582=AXIS2_PLACEMENT_3D('',#579,#580,#581);
#583=CIRCLE('',#582,1.7);
#584=CARTESIAN_POINT('',(0.843274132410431,1.47610593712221,0.));
#585=VERTEX_POINT('',#584);
#586=EDGE_CURVE('E502',#576,#585,#583,.T.);
#587=ORIENTED_EDGE('',*,*,#586,.T.);
#588=DIRECTION('',(-0.587785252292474,-0.809016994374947,0.));
#589=VECTOR('',#588,1.);
#590=CARTESIAN_POINT('',(0.843274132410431,1.47610593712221,0.));
#591=LINE('',#590,#589);
#592=CARTESIAN_POINT('',(0.546872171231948,1.06814363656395,0.));
#593=VERTEX_POINT('',#592);
#594=EDGE_CURVE('E513',#585,#593,#591,.T.);
#595=ORIENTED_EDGE('',*,*,#594,.T.);
#596=CARTESIAN_POINT('',(0.185410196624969,1.18558975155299,0.));
#597=VERTEX_POINT('',#596);
#598=EDGE_CURVE('E552',#593,#597,#363,.T.);
#599=ORIENTED_EDGE('',*,*,#598,.T.);
#600=DIRECTION('',(0.,1.,0.));
#601=VECTOR('',#600,1.);
#602=CARTESIAN_POINT('',(0.185410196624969,1.68985888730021,0.));
#603=LINE('',#602,#601);
#604=CARTESIAN_POINT('',(0.185410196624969,1.68985888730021,0.));
#605=VERTEX_POINT('',#604);
#606=EDGE_CURVE('E531',#597,#605,#603,.T.);
#607=ORIENTED_EDGE('',*,*,#606,.T.);
#608=CARTESIAN_POINT('',(0.,0.,0.));
#609=DIRECTION('',(0.,0.,1.));
#610=DIRECTION('',(1.,0.,0.));
#611=AXIS2_PLACEMENT_3D('',#608,#609,#610);
#612=CIRCLE('',#611,1.7);
#613=CARTESIAN_POINT('',(-0.185410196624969,1.68985888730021,0.));
#614=VERTEX_POINT('',#613);
#615=EDGE_CURVE('E527',#605,#614,#612,.T.);
#616=ORIENTED_EDGE('',*,*,#615,.T.);
#617=DIRECTION('',(0.,-1.,0.));
#618=VECTOR('',#617,1.);
#619=CARTESIAN_POINT('',(-0.185410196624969,1.68985888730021,0.));
#620=LINE('',#619,#618);
#621=CARTESIAN_POINT('',(-0.185410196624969,1.18558975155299,0.));
#622=VERTEX_POINT('',#621);
#623=EDGE_CURVE('E538',#614,#622,#620,.T.);
#624=ORIENTED_EDGE('',*,*,#623,.T.);
#625=CARTESIAN_POINT('',(-0.546872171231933,1.06814363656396,0.));
#626=VERTEX_POINT('',#625);
#627=EDGE_CURVE('E557',#622,#626,#363,.T.);
#628=ORIENTED_EDGE('',*,*,#627,.T.);
#629=DIRECTION('',(-0.587785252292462,0.809016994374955,0.));
#630=VECTOR('',#629,1.);
#631=CARTESIAN_POINT('',(-0.84327413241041,1.47610593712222,0.));
#632=LINE('',#631,#630);
#633=CARTESIAN_POINT('',(-0.84327413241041,1.47610593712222,0.));
#634=VERTEX_POINT('',#633);
#635=EDGE_CURVE('E50',#626,#634,#632,.T.);
#636=ORIENTED_EDGE('',*,*,#635,.T.);
#637=CARTESIAN_POINT('',(0.,0.,0.));
#638=DIRECTION('',(0.,0.,1.));
#639=DIRECTION('',(0.809016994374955,0.587785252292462,0.));
#640=AXIS2_PLACEMENT_3D('',#637,#638,#639);
#641=CIRCLE('',#640,1.7);
#642=EDGE_CURVE('E321',#634,#354,#641,.T.);
#643=ORIENTED_EDGE('',*,*,#642,.T.);
#644=EDGE_LOOP('',(#358,#367,#375,#384,#392,#396,#404,#413,#421,#425,#433,#442,#450,#454,#462,
#471,#479,#483,#491,#500,#508,#512,#520,#529,#537,#541,#549,#558,#566,#570,#578,#587,#595,#599,
#607,#616,#624,#628,#636,#643));
#645=FACE_BOUND('',#644,.T.);
#646=ADVANCED_FACE('F584',(#348,#645),#337,.F.);
#647=CARTESIAN_POINT('',(0.,0.,0.25));
#648=DIRECTION('',(0.,0.,-1.));
#649=DIRECTION('',(-1.,0.,0.));
#650=AXIS2_PLACEMENT_3D('',#647,#648,#649);
#651=CYLINDRICAL_SURFACE('',#650,1.2);
#652=ORIENTED_EDGE('',*,*,#366,.F.);
#653=DIRECTION('',(0.,0.,-1.));
#654=VECTOR('',#653,1.);
#655=CARTESIAN_POINT('',(-0.846872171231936,0.850180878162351,0.25));
#656=LINE('',#655,#654);
#657=EDGE_CURVE('E312',#41,#356,#656,.T.);
#658=ORIENTED_EDGE('',*,*,#657,.F.);
#659=ORIENTED_EDGE('',*,*,#44,.T.);
#660=DIRECTION('',(0.,0.,-1.));
#661=VECTOR('',#660,1.);
#662=CARTESIAN_POINT('',(-1.07026795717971,0.542702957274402,0.25));
#663=LINE('',#662,#661);
#664=EDGE_CURVE('E344',#43,#365,#663,.T.);
#665=ORIENTED_EDGE('',*,*,#664,.T.);
#666=EDGE_LOOP('',(#652,#658,#659,#665));
#667=FACE_BOUND('',#666,.T.);
#668=ADVANCED_FACE('F663',(#667),#651,.F.);
#669=ORIENTED_EDGE('',*,*,#73,.T.);
#670=DIRECTION('',(0.,0.,-1.));
#671=VECTOR('',#670,1.);
#672=CARTESIAN_POINT('',(-0.546872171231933,1.06814363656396,0.25));
#673=LINE('',#672,#671);
#674=EDGE_CURVE('E326',#68,#626,#673,.T.);
#675=ORIENTED_EDGE('',*,*,#674,.T.);
#676=ORIENTED_EDGE('',*,*,#627,.F.);
#677=DIRECTION('',(0.,0.,-1.));
#678=VECTOR('',#677,1.);
#679=CARTESIAN_POINT('',(-0.185410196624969,1.18558975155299,0.25));
#680=LINE('',#679,#678);
#681=EDGE_CURVE('E547',#72,#622,#680,.T.);
#682=ORIENTED_EDGE('',*,*,#681,.F.);
#683=EDGE_LOOP('',(#669,#675,#676,#682));
#684=FACE_BOUND('',#683,.T.);
#685=ADVANCED_FACE('F660',(#684),#651,.F.);
#686=ORIENTED_EDGE('',*,*,#395,.F.);
#687=DIRECTION('',(0.,0.,-1.));
#688=VECTOR('',#687,1.);
#689=CARTESIAN_POINT('',(-1.18485776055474,0.190031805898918,0.25));
#690=LINE('',#689,#688);
#691=EDGE_CURVE('E347',#304,#390,#690,.T.);
#692=ORIENTED_EDGE('',*,*,#691,.F.);
#693=ORIENTED_EDGE('',*,*,#305,.T.);
#694=DIRECTION('',(0.,0.,-1.));
#695=VECTOR('',#694,1.);
#696=CARTESIAN_POINT('',(-1.18485776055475,-0.190031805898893,0.25));
#697=LINE('',#696,#695);
#698=EDGE_CURVE('E369',#300,#394,#697,.T.);
#699=ORIENTED_EDGE('',*,*,#698,.T.);
#700=EDGE_LOOP('',(#686,#692,#693,#699));
#701=FACE_BOUND('',#700,.T.);
#702=ADVANCED_FACE('F593',(#701),#651,.F.);
#703=ORIENTED_EDGE('',*,*,#424,.F.);
#704=DIRECTION('',(0.,0.,-1.));
#705=VECTOR('',#704,1.);
#706=CARTESIAN_POINT('',(-1.07026795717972,-0.542702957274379,0.25));
#707=LINE('',#706,#705);
#708=EDGE_CURVE('E372',#275,#419,#707,.T.);
#709=ORIENTED_EDGE('',*,*,#708,.F.);
#710=ORIENTED_EDGE('',*,*,#276,.T.);
#711=DIRECTION('',(0.,0.,-1.));
#712=VECTOR('',#711,1.);
#713=CARTESIAN_POINT('',(-0.846872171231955,-0.850180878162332,0.25));
#714=LINE('',#713,#712);
#715=EDGE_CURVE('E394',#271,#423,#714,.T.);
#716=ORIENTED_EDGE('',*,*,#715,.T.);
#717=EDGE_LOOP('',(#703,#709,#710,#716));
#718=FACE_BOUND('',#717,.T.);
#719=ADVANCED_FACE('F998',(#718),#651,.F.);
#720=ORIENTED_EDGE('',*,*,#453,.F.);
#721=DIRECTION('',(0.,0.,-1.));
#722=VECTOR('',#721,1.);
#723=CARTESIAN_POINT('',(-0.546872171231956,-1.06814363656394,0.25));
#724=LINE('',#723,#722);
#725=EDGE_CURVE('E397',#246,#448,#724,.T.);
#726=ORIENTED_EDGE('',*,*,#725,.F.);
#727=ORIENTED_EDGE('',*,*,#247,.T.);
#728=DIRECTION('',(0.,0.,-1.));
#729=VECTOR('',#728,1.);
#730=CARTESIAN_POINT('',(-0.185410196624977,-1.18558975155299,0.25));
#731=LINE('',#730,#729);
#732=EDGE_CURVE('E419',#242,#452,#731,.T.);
#733=ORIENTED_EDGE('',*,*,#732,.T.);
#734=EDGE_LOOP('',(#720,#726,#727,#733));
#735=FACE_BOUND('',#734,.T.);
#736=ADVANCED_FACE('F1005',(#735),#651,.F.);
#737=ORIENTED_EDGE('',*,*,#482,.F.);
#738=DIRECTION('',(0.,0.,-1.));
#739=VECTOR('',#738,1.);
#740=CARTESIAN_POINT('',(0.185410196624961,-1.185589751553,0.25));
#741=LINE('',#740,#739);
#742=EDGE_CURVE('E422',#217,#477,#741,.T.);
#743=ORIENTED_EDGE('',*,*,#742,.F.);
#744=ORIENTED_EDGE('',*,*,#218,.T.);
#745=DIRECTION('',(0.,0.,-1.));
#746=VECTOR('',#745,1.);
#747=CARTESIAN_POINT('',(0.546872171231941,-1.06814363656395,0.25));
#748=LINE('',#747,#746);
#749=EDGE_CURVE('E444',#213,#481,#748,.T.);
#750=ORIENTED_EDGE('',*,*,#749,.T.);
#751=EDGE_LOOP('',(#737,#743,#744,#750));
#752=FACE_BOUND('',#751,.T.);
#753=ADVANCED_FACE('F1012',(#752),#651,.F.);
#754=ORIENTED_EDGE('',*,*,#511,.F.);
#755=DIRECTION('',(0.,0.,-1.));
#756=VECTOR('',#755,1.);
#757=CARTESIAN_POINT('',(0.846872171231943,-0.850180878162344,0.25));
#758=LINE('',#757,#756);
#759=EDGE_CURVE('E447',#188,#506,#758,.T.);
#760=ORIENTED_EDGE('',*,*,#759,.F.);
#761=ORIENTED_EDGE('',*,*,#189,.T.);
#762=DIRECTION('',(0.,0.,-1.));
#763=VECTOR('',#762,1.);
#764=CARTESIAN_POINT('',(1.07026795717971,-0.542702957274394,0.25));
#765=LINE('',#764,#763);
#766=EDGE_CURVE('E469',#184,#510,#765,.T.);
#767=ORIENTED_EDGE('',*,*,#766,.T.);
#768=EDGE_LOOP('',(#754,#760,#761,#767));
#769=FACE_BOUND('',#768,.T.);
#770=ADVANCED_FACE('F1019',(#769),#651,.F.);
#771=ORIENTED_EDGE('',*,*,#540,.F.);
#772=DIRECTION('',(0.,0.,-1.));
#773=VECTOR('',#772,1.);
#774=CARTESIAN_POINT('',(1.18485776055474,-0.19003180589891,0.25));
#775=LINE('',#774,#773);
#776=EDGE_CURVE('E472',#159,#535,#775,.T.);
#777=ORIENTED_EDGE('',*,*,#776,.F.);
#778=ORIENTED_EDGE('',*,*,#160,.T.);
#779=DIRECTION('',(0.,0.,-1.));
#780=VECTOR('',#779,1.);
#781=CARTESIAN_POINT('',(1.18485776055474,0.190031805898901,0.25));
#782=LINE('',#781,#780);
#783=EDGE_CURVE('E494',#155,#539,#782,.T.);
#784=ORIENTED_EDGE('',*,*,#783,.T.);
#785=EDGE_LOOP('',(#771,#777,#778,#784));
#786=FACE_BOUND('',#785,.T.);
#787=ADVANCED_FACE('F1026',(#786),#651,.F.);
#788=ORIENTED_EDGE('',*,*,#569,.F.);
#789=DIRECTION('',(0.,0.,-1.));
#790=VECTOR('',#789,1.);
#791=CARTESIAN_POINT('',(1.07026795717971,0.542702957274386,0.25));
#792=LINE('',#791,#790);
#793=EDGE_CURVE('E497',#130,#564,#792,.T.);
#794=ORIENTED_EDGE('',*,*,#793,.F.);
#795=ORIENTED_EDGE('',*,*,#131,.T.);
#796=DIRECTION('',(0.,0.,-1.));
#797=VECTOR('',#796,1.);
#798=CARTESIAN_POINT('',(0.846872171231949,0.850180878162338,0.25));
#799=LINE('',#798,#797);
#800=EDGE_CURVE('E519',#126,#568,#799,.T.);
#801=ORIENTED_EDGE('',*,*,#800,.T.);
#802=EDGE_LOOP('',(#788,#794,#795,#801));
#803=FACE_BOUND('',#802,.T.);
#804=ADVANCED_FACE('F626',(#803),#651,.F.);
#805=ORIENTED_EDGE('',*,*,#598,.F.);
#806=DIRECTION('',(0.,0.,-1.));
#807=VECTOR('',#806,1.);
#808=CARTESIAN_POINT('',(0.546872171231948,1.06814363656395,0.25));
#809=LINE('',#808,#807);
#810=EDGE_CURVE('E522',#101,#593,#809,.T.);
#811=ORIENTED_EDGE('',*,*,#810,.F.);
#812=ORIENTED_EDGE('',*,*,#102,.T.);
#813=DIRECTION('',(0.,0.,-1.));
#814=VECTOR('',#813,1.);
#815=CARTESIAN_POINT('',(0.185410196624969,1.18558975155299,0.25));
#816=LINE('',#815,#814);
#817=EDGE_CURVE('E544',#97,#597,#816,.T.);
#818=ORIENTED_EDGE('',*,*,#817,.T.);
#819=EDGE_LOOP('',(#805,#811,#812,#818));
#820=FACE_BOUND('',#819,.T.);
#821=ADVANCED_FACE('F643',(#820),#651,.F.);
#822=CARTESIAN_POINT('',(0.,0.,0.25));
#823=DIRECTION('',(0.,0.,-1.));
#824=DIRECTION('',(-1.,0.,0.));
#825=AXIS2_PLACEMENT_3D('',#822,#823,#824);
#826=CYLINDRICAL_SURFACE('',#825,2.2);
#827=ORIENTED_EDGE('',*,*,#31,.F.);
#828=EDGE_LOOP('',(#827));
#829=FACE_BOUND('',#828,.T.);
#830=ORIENTED_EDGE('',*,*,#345,.T.);
#831=EDGE_LOOP('',(#830));
#832=FACE_BOUND('',#831,.T.);
#833=ADVANCED_FACE('F37',(#829,#832),#826,.T.);
#834=CARTESIAN_POINT('',(0.,0.,0.25));
#835=DIRECTION('',(0.,0.,-1.));
#836=DIRECTION('',(-1.,0.,0.));
#837=AXIS2_PLACEMENT_3D('',#834,#835,#836);
#838=CYLINDRICAL_SURFACE('',#837,1.7);
#839=ORIENTED_EDGE('',*,*,#615,.F.);
#840=DIRECTION('',(0.,0.,-1.));
#841=VECTOR('',#840,1.);
#842=CARTESIAN_POINT('',(0.185410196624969,1.68985888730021,0.25));
#843=LINE('',#842,#841);
#844=EDGE_CURVE('E535',#89,#605,#843,.T.);
#845=ORIENTED_EDGE('',*,*,#844,.F.);
#846=ORIENTED_EDGE('',*,*,#90,.T.);
#847=DIRECTION('',(0.,0.,-1.));
#848=VECTOR('',#847,1.);
#849=CARTESIAN_POINT('',(-0.185410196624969,1.68985888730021,0.25));
#850=LINE('',#849,#848);
#851=EDGE_CURVE('E549',#80,#614,#850,.T.);
#852=ORIENTED_EDGE('',*,*,#851,.T.);
#853=EDGE_LOOP('',(#839,#845,#846,#852));
#854=FACE_BOUND('',#853,.T.);
#855=ADVANCED_FACE('F655',(#854),#838,.F.);
#856=CARTESIAN_POINT('',(-0.185410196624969,1.68985888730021,0.25));
#857=DIRECTION('',(1.,0.,0.));
#858=DIRECTION('',(0.,1.,0.));
#859=AXIS2_PLACEMENT_3D('',#856,#857,#858);
#860=PLANE('',#859);
#861=ORIENTED_EDGE('',*,*,#623,.F.);
#862=ORIENTED_EDGE('',*,*,#851,.F.);
#863=ORIENTED_EDGE('',*,*,#81,.T.);
#864=ORIENTED_EDGE('',*,*,#681,.T.);
#865=EDGE_LOOP('',(#861,#862,#863,#864));
#866=FACE_BOUND('',#865,.T.);
#867=ADVANCED_FACE('F657',(#866),#860,.T.);
#868=CARTESIAN_POINT('',(0.185410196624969,1.68985888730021,0.25));
#869=DIRECTION('',(-1.,0.,0.));
#870=DIRECTION('',(0.,-1.,0.));
#871=AXIS2_PLACEMENT_3D('',#868,#869,#870);
#872=PLANE('',#871);
#873=ORIENTED_EDGE('',*,*,#606,.F.);
#874=ORIENTED_EDGE('',*,*,#817,.F.);
#875=ORIENTED_EDGE('',*,*,#98,.T.);
#876=ORIENTED_EDGE('',*,*,#844,.T.);
#877=EDGE_LOOP('',(#873,#874,#875,#876));
#878=FACE_BOUND('',#877,.T.);
#879=ADVANCED_FACE('F647',(#878),#872,.T.);
#880=CARTESIAN_POINT('',(0.,0.,0.25));
#881=DIRECTION('',(0.,0.,-1.));
#882=DIRECTION('',(-1.,0.,0.));
#883=AXIS2_PLACEMENT_3D('',#880,#881,#882);
#884=CYLINDRICAL_SURFACE('',#883,1.7);
#885=ORIENTED_EDGE('',*,*,#586,.F.);
#886=DIRECTION('',(0.,0.,-1.));
#887=VECTOR('',#886,1.);
#888=CARTESIAN_POINT('',(1.14327413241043,1.2581431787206,0.25));
#889=LINE('',#888,#887);
#890=EDGE_CURVE('E510',#118,#576,#889,.T.);
#891=ORIENTED_EDGE('',*,*,#890,.F.);
#892=ORIENTED_EDGE('',*,*,#119,.T.);
#893=DIRECTION('',(0.,0.,-1.));
#894=VECTOR('',#893,1.);
#895=CARTESIAN_POINT('',(0.843274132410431,1.47610593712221,0.25));
#896=LINE('',#895,#894);
#897=EDGE_CURVE('E524',#109,#585,#896,.T.);
#898=ORIENTED_EDGE('',*,*,#897,.T.);
#899=EDGE_LOOP('',(#885,#891,#892,#898));
#900=FACE_BOUND('',#899,.T.);
#901=ADVANCED_FACE('F638',(#900),#884,.F.);
#902=CARTESIAN_POINT('',(0.843274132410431,1.47610593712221,0.25));
#903=DIRECTION('',(0.809016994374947,-0.587785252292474,0.));
#904=DIRECTION('',(0.587785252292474,0.809016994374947,0.));
#905=AXIS2_PLACEMENT_3D('',#902,#903,#904);
#906=PLANE('',#905);
#907=ORIENTED_EDGE('',*,*,#594,.F.);
#908=ORIENTED_EDGE('',*,*,#897,.F.);
#909=ORIENTED_EDGE('',*,*,#110,.T.);
#910=ORIENTED_EDGE('',*,*,#810,.T.);
#911=EDGE_LOOP('',(#907,#908,#909,#910));
#912=FACE_BOUND('',#911,.T.);
#913=ADVANCED_FACE('F640',(#912),#906,.T.);
#914=CARTESIAN_POINT('',(1.14327413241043,1.2581431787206,0.25));
#915=DIRECTION('',(-0.809016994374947,0.587785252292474,0.));
#916=DIRECTION('',(-0.587785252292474,-0.809016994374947,0.));
#917=AXIS2_PLACEMENT_3D('',#914,#915,#916);
#918=PLANE('',#917);
#919=ORIENTED_EDGE('',*,*,#577,.F.);
#920=ORIENTED_EDGE('',*,*,#800,.F.);
#921=ORIENTED_EDGE('',*,*,#127,.T.);
#922=ORIENTED_EDGE('',*,*,#890,.T.);
#923=EDGE_LOOP('',(#919,#920,#921,#922));
#924=FACE_BOUND('',#923,.T.);
#925=ADVANCED_FACE('F630',(#924),#918,.T.);
#926=CARTESIAN_POINT('',(0.,0.,0.25));
#927=DIRECTION('',(0.,0.,-1.));
#928=DIRECTION('',(-1.,0.,0.));
#929=AXIS2_PLACEMENT_3D('',#926,#927,#928);
#930=CYLINDRICAL_SURFACE('',#929,1.7);
#931=ORIENTED_EDGE('',*,*,#557,.F.);
#932=DIRECTION('',(0.,0.,-1.));
#933=VECTOR('',#932,1.);
#934=CARTESIAN_POINT('',(1.66444620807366,0.345859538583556,0.25));
#935=LINE('',#934,#933);
#936=EDGE_CURVE('E485',#147,#547,#935,.T.);
#937=ORIENTED_EDGE('',*,*,#936,.F.);
#938=ORIENTED_EDGE('',*,*,#148,.T.);
#939=DIRECTION('',(0.,0.,-1.));
#940=VECTOR('',#939,1.);
#941=CARTESIAN_POINT('',(1.54985640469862,0.698530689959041,0.25));
#942=LINE('',#941,#940);
#943=EDGE_CURVE('E499',#138,#556,#942,.T.);
#944=ORIENTED_EDGE('',*,*,#943,.T.);
#945=EDGE_LOOP('',(#931,#937,#938,#944));
#946=FACE_BOUND('',#945,.T.);
#947=ADVANCED_FACE('F705',(#946),#930,.F.);
#948=CARTESIAN_POINT('',(1.54985640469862,0.698530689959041,0.25));
#949=DIRECTION('',(0.309016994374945,-0.951056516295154,0.));
#950=DIRECTION('',(0.951056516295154,0.309016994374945,0.));
#951=AXIS2_PLACEMENT_3D('',#948,#949,#950);
#952=PLANE('',#951);
#953=ORIENTED_EDGE('',*,*,#565,.F.);
#954=ORIENTED_EDGE('',*,*,#943,.F.);
#955=ORIENTED_EDGE('',*,*,#139,.T.);
#956=ORIENTED_EDGE('',*,*,#793,.T.);
#957=EDGE_LOOP('',(#953,#954,#955,#956));
#958=FACE_BOUND('',#957,.T.);
#959=ADVANCED_FACE('F708',(#958),#952,.T.);
#960=CARTESIAN_POINT('',(1.66444620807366,0.345859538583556,0.25));
#961=DIRECTION('',(-0.309016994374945,0.951056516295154,0.));
#962=DIRECTION('',(-0.951056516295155,-0.309016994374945,0.));
#963=AXIS2_PLACEMENT_3D('',#960,#961,#962);
#964=PLANE('',#963);
#965=ORIENTED_EDGE('',*,*,#548,.F.);
#966=ORIENTED_EDGE('',*,*,#783,.F.);
#967=ORIENTED_EDGE('',*,*,#156,.T.);
#968=ORIENTED_EDGE('',*,*,#936,.T.);
#969=EDGE_LOOP('',(#965,#966,#967,#968));
#970=FACE_BOUND('',#969,.T.);
#971=ADVANCED_FACE('F712',(#970),#964,.T.);
#972=CARTESIAN_POINT('',(0.,0.,0.25));
#973=DIRECTION('',(0.,0.,-1.));
#974=DIRECTION('',(-1.,0.,0.));
#975=AXIS2_PLACEMENT_3D('',#972,#973,#974);
#976=CYLINDRICAL_SURFACE('',#975,1.7);
#977=ORIENTED_EDGE('',*,*,#528,.F.);
#978=DIRECTION('',(0.,0.,-1.));
#979=VECTOR('',#978,1.);
#980=CARTESIAN_POINT('',(1.54985640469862,-0.698530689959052,0.25));
#981=LINE('',#980,#979);
#982=EDGE_CURVE('E460',#176,#518,#981,.T.);
#983=ORIENTED_EDGE('',*,*,#982,.F.);
#984=ORIENTED_EDGE('',*,*,#177,.T.);
#985=DIRECTION('',(0.,0.,-1.));
#986=VECTOR('',#985,1.);
#987=CARTESIAN_POINT('',(1.66444620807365,-0.345859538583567,0.25));
#988=LINE('',#987,#986);
#989=EDGE_CURVE('E474',#167,#527,#988,.T.);
#990=ORIENTED_EDGE('',*,*,#989,.T.);
#991=EDGE_LOOP('',(#977,#983,#984,#990));
#992=FACE_BOUND('',#991,.T.);
#993=ADVANCED_FACE('F716',(#992),#976,.F.);
#994=CARTESIAN_POINT('',(1.66444620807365,-0.345859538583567,0.25));
#995=DIRECTION('',(-0.309016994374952,-0.951056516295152,0.));
#996=DIRECTION('',(0.951056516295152,-0.309016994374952,0.));
#997=AXIS2_PLACEMENT_3D('',#994,#995,#996);
#998=PLANE('',#997);
#999=ORIENTED_EDGE('',*,*,#536,.F.);
#1000=ORIENTED_EDGE('',*,*,#989,.F.);
#1001=ORIENTED_EDGE('',*,*,#168,.T.);
#1002=ORIENTED_EDGE('',*,*,#776,.T.);
#1003=EDGE_LOOP('',(#999,#1000,#1001,#1002));
#1004=FACE_BOUND('',#1003,.T.);
#1005=ADVANCED_FACE('F720',(#1004),#998,.T.);
#1006=CARTESIAN_POINT('',(1.54985640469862,-0.698530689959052,0.25));
#1007=DIRECTION('',(0.309016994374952,0.951056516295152,0.));
#1008=DIRECTION('',(-0.951056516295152,0.309016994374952,0.));
#1009=AXIS2_PLACEMENT_3D('',#1006,#1007,#1008);
#1010=PLANE('',#1009);
#1011=ORIENTED_EDGE('',*,*,#519,.F.);
#1012=ORIENTED_EDGE('',*,*,#766,.F.);
#1013=ORIENTED_EDGE('',*,*,#185,.T.);
#1014=ORIENTED_EDGE('',*,*,#982,.T.);
#1015=EDGE_LOOP('',(#1011,#1012,#1013,#1014));
#1016=FACE_BOUND('',#1015,.T.);
#1017=ADVANCED_FACE('F724',(#1016),#1010,.T.);
#1018=CARTESIAN_POINT('',(0.,0.,0.25));
#1019=DIRECTION('',(0.,0.,-1.));
#1020=DIRECTION('',(-1.,0.,0.));
#1021=AXIS2_PLACEMENT_3D('',#1018,#1019,#1020);
#1022=CYLINDRICAL_SURFACE('',#1021,1.7);
#1023=ORIENTED_EDGE('',*,*,#499,.F.);
#1024=DIRECTION('',(0.,0.,-1.));
#1025=VECTOR('',#1024,1.);
#1026=CARTESIAN_POINT('',(0.843274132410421,-1.47610593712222,0.25));
#1027=LINE('',#1026,#1025);
#1028=EDGE_CURVE('E435',#205,#489,#1027,.T.);
#1029=ORIENTED_EDGE('',*,*,#1028,.F.);
#1030=ORIENTED_EDGE('',*,*,#206,.T.);
#1031=DIRECTION('',(0.,0.,-1.));
#1032=VECTOR('',#1031,1.);
#1033=CARTESIAN_POINT('',(1.14327413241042,-1.25814317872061,0.25));
#1034=LINE('',#1033,#1032);
#1035=EDGE_CURVE('E449',#196,#498,#1034,.T.);
#1036=ORIENTED_EDGE('',*,*,#1035,.T.);
#1037=EDGE_LOOP('',(#1023,#1029,#1030,#1036));
#1038=FACE_BOUND('',#1037,.T.);
#1039=ADVANCED_FACE('F728',(#1038),#1022,.F.);
#1040=CARTESIAN_POINT('',(1.14327413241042,-1.25814317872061,0.25));
#1041=DIRECTION('',(-0.809016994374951,-0.587785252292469,0.));
#1042=DIRECTION('',(0.587785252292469,-0.809016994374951,0.));
#1043=AXIS2_PLACEMENT_3D('',#1040,#1041,#1042);
#1044=PLANE('',#1043);
#1045=ORIENTED_EDGE('',*,*,#507,.F.);
#1046=ORIENTED_EDGE('',*,*,#1035,.F.);
#1047=ORIENTED_EDGE('',*,*,#197,.T.);
#1048=ORIENTED_EDGE('',*,*,#759,.T.);
#1049=EDGE_LOOP('',(#1045,#1046,#1047,#1048));
#1050=FACE_BOUND('',#1049,.T.);
#1051=ADVANCED_FACE('F732',(#1050),#1044,.T.);
#1052=CARTESIAN_POINT('',(0.843274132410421,-1.47610593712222,0.25));
#1053=DIRECTION('',(0.809016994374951,0.587785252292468,0.));
#1054=DIRECTION('',(-0.587785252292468,0.809016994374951,0.));
#1055=AXIS2_PLACEMENT_3D('',#1052,#1053,#1054);
#1056=PLANE('',#1055);
#1057=ORIENTED_EDGE('',*,*,#490,.F.);
#1058=ORIENTED_EDGE('',*,*,#749,.F.);
#1059=ORIENTED_EDGE('',*,*,#214,.T.);
#1060=ORIENTED_EDGE('',*,*,#1028,.T.);
#1061=EDGE_LOOP('',(#1057,#1058,#1059,#1060));
#1062=FACE_BOUND('',#1061,.T.);
#1063=ADVANCED_FACE('F736',(#1062),#1056,.T.);
#1064=CARTESIAN_POINT('',(0.,0.,0.25));
#1065=DIRECTION('',(0.,0.,-1.));
#1066=DIRECTION('',(-1.,0.,0.));
#1067=AXIS2_PLACEMENT_3D('',#1064,#1065,#1066);
#1068=CYLINDRICAL_SURFACE('',#1067,1.7);
#1069=ORIENTED_EDGE('',*,*,#470,.F.);
#1070=DIRECTION('',(0.,0.,-1.));
#1071=VECTOR('',#1070,1.);
#1072=CARTESIAN_POINT('',(-0.185410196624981,-1.6898588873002,0.25));
#1073=LINE('',#1072,#1071);
#1074=EDGE_CURVE('E410',#234,#460,#1073,.T.);
#1075=ORIENTED_EDGE('',*,*,#1074,.F.);
#1076=ORIENTED_EDGE('',*,*,#235,.T.);
#1077=DIRECTION('',(0.,0.,-1.));
#1078=VECTOR('',#1077,1.);
#1079=CARTESIAN_POINT('',(0.185410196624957,-1.68985888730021,0.25));
#1080=LINE('',#1079,#1078);
#1081=EDGE_CURVE('E424',#225,#469,#1080,.T.);
#1082=ORIENTED_EDGE('',*,*,#1081,.T.);
#1083=EDGE_LOOP('',(#1069,#1075,#1076,#1082));
#1084=FACE_BOUND('',#1083,.T.);
#1085=ADVANCED_FACE('F740',(#1084),#1068,.F.);
#1086=CARTESIAN_POINT('',(0.185410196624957,-1.68985888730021,0.25));
#1087=DIRECTION('',(-1.,0.,0.));
#1088=DIRECTION('',(0.,-1.,0.));
#1089=AXIS2_PLACEMENT_3D('',#1086,#1087,#1088);
#1090=PLANE('',#1089);
#1091=ORIENTED_EDGE('',*,*,#478,.F.);
#1092=ORIENTED_EDGE('',*,*,#1081,.F.);
#1093=ORIENTED_EDGE('',*,*,#226,.T.);
#1094=ORIENTED_EDGE('',*,*,#742,.T.);
#1095=EDGE_LOOP('',(#1091,#1092,#1093,#1094));
#1096=FACE_BOUND('',#1095,.T.);
#1097=ADVANCED_FACE('F744',(#1096),#1090,.T.);
#1098=CARTESIAN_POINT('',(-0.185410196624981,-1.6898588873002,0.25));
#1099=DIRECTION('',(1.,0.,0.));
#1100=DIRECTION('',(0.,1.,0.));
#1101=AXIS2_PLACEMENT_3D('',#1098,#1099,#1100);
#1102=PLANE('',#1101);
#1103=ORIENTED_EDGE('',*,*,#461,.F.);
#1104=ORIENTED_EDGE('',*,*,#732,.F.);
#1105=ORIENTED_EDGE('',*,*,#243,.T.);
#1106=ORIENTED_EDGE('',*,*,#1074,.T.);
#1107=EDGE_LOOP('',(#1103,#1104,#1105,#1106));
#1108=FACE_BOUND('',#1107,.T.);
#1109=ADVANCED_FACE('F748',(#1108),#1102,.T.);
#1110=CARTESIAN_POINT('',(0.,0.,0.25));
#1111=DIRECTION('',(0.,0.,-1.));
#1112=DIRECTION('',(-1.,0.,0.));
#1113=AXIS2_PLACEMENT_3D('',#1110,#1111,#1112);
#1114=CYLINDRICAL_SURFACE('',#1113,1.7);
#1115=ORIENTED_EDGE('',*,*,#441,.F.);
#1116=DIRECTION('',(0.,0.,-1.));
#1117=VECTOR('',#1116,1.);
#1118=CARTESIAN_POINT('',(-1.14327413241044,-1.25814317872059,0.25));
#1119=LINE('',#1118,#1117);
#1120=EDGE_CURVE('E385',#263,#431,#1119,.T.);
#1121=ORIENTED_EDGE('',*,*,#1120,.F.);
#1122=ORIENTED_EDGE('',*,*,#264,.T.);
#1123=DIRECTION('',(0.,0.,-1.));
#1124=VECTOR('',#1123,1.);
#1125=CARTESIAN_POINT('',(-0.843274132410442,-1.4761059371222,0.25));
#1126=LINE('',#1125,#1124);
#1127=EDGE_CURVE('E399',#254,#440,#1126,.T.);
#1128=ORIENTED_EDGE('',*,*,#1127,.T.);
#1129=EDGE_LOOP('',(#1115,#1121,#1122,#1128));
#1130=FACE_BOUND('',#1129,.T.);
#1131=ADVANCED_FACE('F752',(#1130),#1114,.F.);
#1132=CARTESIAN_POINT('',(-0.843274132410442,-1.4761059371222,0.25));
#1133=DIRECTION('',(-0.809016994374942,0.58778525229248,0.));
#1134=DIRECTION('',(-0.58778525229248,-0.809016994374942,0.));
#1135=AXIS2_PLACEMENT_3D('',#1132,#1133,#1134);
#1136=PLANE('',#1135);
#1137=ORIENTED_EDGE('',*,*,#449,.F.);
#1138=ORIENTED_EDGE('',*,*,#1127,.F.);
#1139=ORIENTED_EDGE('',*,*,#255,.T.);
#1140=ORIENTED_EDGE('',*,*,#725,.T.);
#1141=EDGE_LOOP('',(#1137,#1138,#1139,#1140));
#1142=FACE_BOUND('',#1141,.T.);
#1143=ADVANCED_FACE('F756',(#1142),#1136,.T.);
#1144=CARTESIAN_POINT('',(-1.14327413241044,-1.25814317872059,0.25));
#1145=DIRECTION('',(0.809016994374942,-0.58778525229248,0.));
#1146=DIRECTION('',(0.58778525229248,0.809016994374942,0.));
#1147=AXIS2_PLACEMENT_3D('',#1144,#1145,#1146);
#1148=PLANE('',#1147);
#1149=ORIENTED_EDGE('',*,*,#432,.F.);
#1150=ORIENTED_EDGE('',*,*,#715,.F.);
#1151=ORIENTED_EDGE('',*,*,#272,.T.);
#1152=ORIENTED_EDGE('',*,*,#1120,.T.);
#1153=EDGE_LOOP('',(#1149,#1150,#1151,#1152));
#1154=FACE_BOUND('',#1153,.T.);
#1155=ADVANCED_FACE('F760',(#1154),#1148,.T.);
#1156=CARTESIAN_POINT('',(0.,0.,0.25));
#1157=DIRECTION('',(0.,0.,-1.));
#1158=DIRECTION('',(-1.,0.,0.));
#1159=AXIS2_PLACEMENT_3D('',#1156,#1157,#1158);
#1160=CYLINDRICAL_SURFACE('',#1159,1.7);
#1161=ORIENTED_EDGE('',*,*,#412,.F.);
#1162=DIRECTION('',(0.,0.,-1.));
#1163=VECTOR('',#1162,1.);
#1164=CARTESIAN_POINT('',(-1.66444620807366,-0.345859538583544,0.25));
#1165=LINE('',#1164,#1163);
#1166=EDGE_CURVE('E360',#292,#402,#1165,.T.);
#1167=ORIENTED_EDGE('',*,*,#1166,.F.);
#1168=ORIENTED_EDGE('',*,*,#293,.T.);
#1169=DIRECTION('',(0.,0.,-1.));
#1170=VECTOR('',#1169,1.);
#1171=CARTESIAN_POINT('',(-1.54985640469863,-0.69853068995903,0.25));
#1172=LINE('',#1171,#1170);
#1173=EDGE_CURVE('E374',#283,#411,#1172,.T.);
#1174=ORIENTED_EDGE('',*,*,#1173,.T.);
#1175=EDGE_LOOP('',(#1161,#1167,#1168,#1174));
#1176=FACE_BOUND('',#1175,.T.);
#1177=ADVANCED_FACE('F764',(#1176),#1160,.F.);
#1178=CARTESIAN_POINT('',(-1.54985640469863,-0.69853068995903,0.25));
#1179=DIRECTION('',(-0.309016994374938,0.951056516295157,0.));
#1180=DIRECTION('',(-0.951056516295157,-0.309016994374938,0.));
#1181=AXIS2_PLACEMENT_3D('',#1178,#1179,#1180);
#1182=PLANE('',#1181);
#1183=ORIENTED_EDGE('',*,*,#420,.F.);
#1184=ORIENTED_EDGE('',*,*,#1173,.F.);
#1185=ORIENTED_EDGE('',*,*,#284,.T.);
#1186=ORIENTED_EDGE('',*,*,#708,.T.);
#1187=EDGE_LOOP('',(#1183,#1184,#1185,#1186));
#1188=FACE_BOUND('',#1187,.T.);
#1189=ADVANCED_FACE('F768',(#1188),#1182,.T.);
#1190=CARTESIAN_POINT('',(-1.66444620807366,-0.345859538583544,0.25));
#1191=DIRECTION('',(0.309016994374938,-0.951056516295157,0.));
#1192=DIRECTION('',(0.951056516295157,0.309016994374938,0.));
#1193=AXIS2_PLACEMENT_3D('',#1190,#1191,#1192);
#1194=PLANE('',#1193);
#1195=ORIENTED_EDGE('',*,*,#403,.F.);
#1196=ORIENTED_EDGE('',*,*,#698,.F.);
#1197=ORIENTED_EDGE('',*,*,#301,.T.);
#1198=ORIENTED_EDGE('',*,*,#1166,.T.);
#1199=EDGE_LOOP('',(#1195,#1196,#1197,#1198));
#1200=FACE_BOUND('',#1199,.T.);
#1201=ADVANCED_FACE('F589',(#1200),#1194,.T.);
#1202=CARTESIAN_POINT('',(0.,0.,0.25));
#1203=DIRECTION('',(0.,0.,-1.));
#1204=DIRECTION('',(-1.,0.,0.));
#1205=AXIS2_PLACEMENT_3D('',#1202,#1203,#1204);
#1206=CYLINDRICAL_SURFACE('',#1205,1.7);
#1207=ORIENTED_EDGE('',*,*,#383,.F.);
#1208=DIRECTION('',(0.,0.,-1.));
#1209=VECTOR('',#1208,1.);
#1210=CARTESIAN_POINT('',(-1.54985640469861,0.698530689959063,0.25));
#1211=LINE('',#1210,#1209);
#1212=EDGE_CURVE('E336',#321,#373,#1211,.T.);
#1213=ORIENTED_EDGE('',*,*,#1212,.F.);
#1214=ORIENTED_EDGE('',*,*,#322,.T.);
#1215=DIRECTION('',(0.,0.,-1.));
#1216=VECTOR('',#1215,1.);
#1217=CARTESIAN_POINT('',(-1.66444620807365,0.345859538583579,0.25));
#1218=LINE('',#1217,#1216);
#1219=EDGE_CURVE('E349',#312,#382,#1218,.T.);
#1220=ORIENTED_EDGE('',*,*,#1219,.T.);
#1221=EDGE_LOOP('',(#1207,#1213,#1214,#1220));
#1222=FACE_BOUND('',#1221,.T.);
#1223=ADVANCED_FACE('F672',(#1222),#1206,.F.);
#1224=CARTESIAN_POINT('',(-1.66444620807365,0.345859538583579,0.25));
#1225=DIRECTION('',(0.309016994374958,0.95105651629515,0.));
#1226=DIRECTION('',(-0.95105651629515,0.309016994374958,0.));
#1227=AXIS2_PLACEMENT_3D('',#1224,#1225,#1226);
#1228=PLANE('',#1227);
#1229=ORIENTED_EDGE('',*,*,#391,.F.);
#1230=ORIENTED_EDGE('',*,*,#1219,.F.);
#1231=ORIENTED_EDGE('',*,*,#313,.T.);
#1232=ORIENTED_EDGE('',*,*,#691,.T.);
#1233=EDGE_LOOP('',(#1229,#1230,#1231,#1232));
#1234=FACE_BOUND('',#1233,.T.);
#1235=ADVANCED_FACE('F674',(#1234),#1228,.T.);
#1236=CARTESIAN_POINT('',(-1.54985640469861,0.698530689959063,0.25));
#1237=DIRECTION('',(-0.309016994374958,-0.95105651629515,0.));
#1238=DIRECTION('',(0.95105651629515,-0.309016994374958,0.));
#1239=AXIS2_PLACEMENT_3D('',#1236,#1237,#1238);
#1240=PLANE('',#1239);
#1241=ORIENTED_EDGE('',*,*,#374,.F.);
#1242=ORIENTED_EDGE('',*,*,#664,.F.);
#1243=ORIENTED_EDGE('',*,*,#328,.T.);
#1244=ORIENTED_EDGE('',*,*,#1212,.T.);
#1245=EDGE_LOOP('',(#1241,#1242,#1243,#1244));
#1246=FACE_BOUND('',#1245,.T.);
#1247=ADVANCED_FACE('F666',(#1246),#1240,.T.);
#1248=CARTESIAN_POINT('',(0.,0.,0.25));
#1249=DIRECTION('',(0.,0.,-1.));
#1250=DIRECTION('',(-1.,0.,0.));
#1251=AXIS2_PLACEMENT_3D('',#1248,#1249,#1250);
#1252=CYLINDRICAL_SURFACE('',#1251,1.7);
#1253=ORIENTED_EDGE('',*,*,#642,.F.);
#1254=DIRECTION('',(0.,0.,-1.));
#1255=VECTOR('',#1254,1.);
#1256=CARTESIAN_POINT('',(-0.84327413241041,1.47610593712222,0.25));
#1257=LINE('',#1256,#1255);
#1258=EDGE_CURVE('E301',#60,#634,#1257,.T.);
#1259=ORIENTED_EDGE('',*,*,#1258,.F.);
#1260=ORIENTED_EDGE('',*,*,#61,.T.);
#1261=DIRECTION('',(0.,0.,-1.));
#1262=VECTOR('',#1261,1.);
#1263=CARTESIAN_POINT('',(-1.14327413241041,1.25814317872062,0.25));
#1264=LINE('',#1263,#1262);
#1265=EDGE_CURVE('E299',#51,#354,#1264,.T.);
#1266=ORIENTED_EDGE('',*,*,#1265,.T.);
#1267=EDGE_LOOP('',(#1253,#1259,#1260,#1266));
#1268=FACE_BOUND('',#1267,.T.);
#1269=ADVANCED_FACE('F298',(#1268),#1252,.F.);
#1270=CARTESIAN_POINT('',(-1.14327413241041,1.25814317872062,0.25));
#1271=DIRECTION('',(0.809016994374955,0.587785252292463,0.));
#1272=DIRECTION('',(-0.587785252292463,0.809016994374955,0.));
#1273=AXIS2_PLACEMENT_3D('',#1270,#1271,#1272);
#1274=PLANE('',#1273);
#1275=ORIENTED_EDGE('',*,*,#357,.F.);
#1276=ORIENTED_EDGE('',*,*,#1265,.F.);
#1277=ORIENTED_EDGE('',*,*,#52,.T.);
#1278=ORIENTED_EDGE('',*,*,#657,.T.);
#1279=EDGE_LOOP('',(#1275,#1276,#1277,#1278));
#1280=FACE_BOUND('',#1279,.T.);
#1281=ADVANCED_FACE('F308',(#1280),#1274,.T.);
#1282=CARTESIAN_POINT('',(-0.84327413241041,1.47610593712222,0.25));
#1283=DIRECTION('',(-0.809016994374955,-0.587785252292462,0.));
#1284=DIRECTION('',(0.587785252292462,-0.809016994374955,0.));
#1285=AXIS2_PLACEMENT_3D('',#1282,#1283,#1284);
#1286=PLANE('',#1285);
#1287=ORIENTED_EDGE('',*,*,#635,.F.);
#1288=ORIENTED_EDGE('',*,*,#674,.F.);
#1289=ORIENTED_EDGE('',*,*,#69,.T.);
#1290=ORIENTED_EDGE('',*,*,#1258,.T.);
#1291=EDGE_LOOP('',(#1287,#1288,#1289,#1290));
#1292=FACE_BOUND('',#1291,.T.);
#1293=ADVANCED_FACE('F661',(#1292),#1286,.T.);
#1294=CLOSED_SHELL('',(#332,#646,#668,#685,#702,#719,#736,#753,#770,#787,#804,#821,#833,#855,
#867,#879,#901,#913,#925,#947,#959,#971,#993,#1005,#1017,#1039,#1051,#1063,#1085,#1097,#1109,
#1131,#1143,#1155,#1177,#1189,#1201,#1223,#1235,#1247,#1269,#1281,#1293));
#1295=MANIFOLD_SOLID_BREP('B2',#1294);
#1296=ADVANCED_BREP_SHAPE_REPRESENTATION('',(#18,#1295),#14);
#1297=SHAPE_DEFINITION_REPRESENTATION(#9,#1296);
ENDSEC;
END-ISO-10303-21;
